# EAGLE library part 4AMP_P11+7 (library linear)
OP AMP

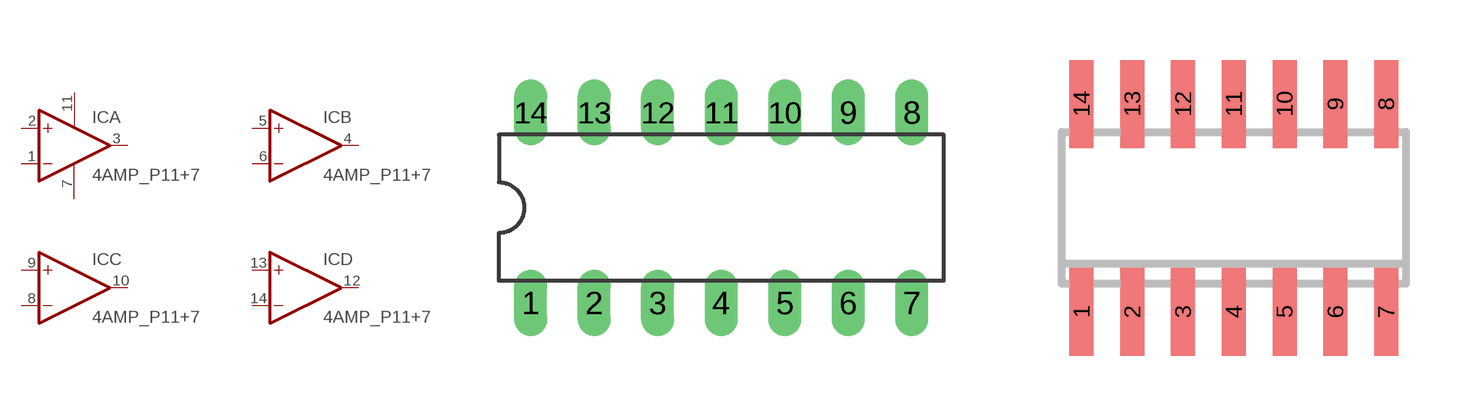
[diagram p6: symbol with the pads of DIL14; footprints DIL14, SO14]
Designator prefix IC; gates A=OPAMP B=OPAMP C=OPAMP D=OPAMP P=PWR+-

## 4AMP_P11+7N  [DIL14]
1  A:-IN  in
2  A:+IN  in
3  A:OUT  out
4  B:OUT  out
5  B:+IN  in
6  B:-IN  in
7  P:V-  pwr
8  C:-IN  in
9  C:+IN  in
10  C:OUT  out
11  P:V+  pwr
12  D:OUT  out
13  D:+IN  in
14  D:-IN  in

## 4AMP_P11+7D  [SO14]
Pads as for DIL14

## Footprint DIL14 (pad centres in mm)
Dual In Line Package
drill 0.813 long: 1 -7.62,-3.81; 2 -5.08,-3.81; 3 -2.54,-3.81; 4 0,-3.81; 5 2.54,-3.81; 6 5.08,-3.81; 7 7.62,-3.81; 8 7.62,3.81; 9 5.08,3.81; 10 2.54,3.81; 11 0,3.81; 12 -2.54,3.81; 13 -5.08,3.81; 14 -7.62,3.81

## Footprint SO14 (pad centres in mm)
Small Outline Package 14
smd 0.6 x 2.2: 1 -3.81,-2.6; 2 -2.54,-2.6; 3 -1.27,-2.6; 4 0,-2.6; 5 1.27,-2.6; 6 2.54,-2.6; 7 3.81,-2.6; 8 3.81,2.6; 9 2.54,2.6; 10 1.27,2.6; 11 0,2.6; 12 -1.27,2.6; 13 -2.54,2.6; 14 -3.81,2.6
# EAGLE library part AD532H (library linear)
MULTIPLIER

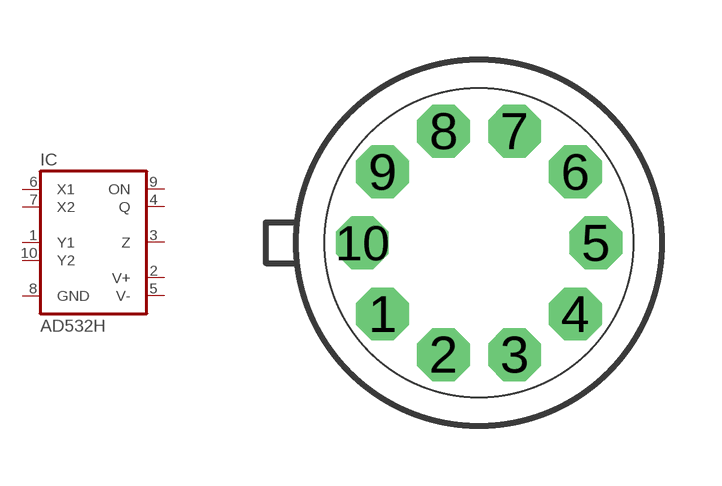
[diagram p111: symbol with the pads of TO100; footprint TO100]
Designator prefix IC

## AD532H  [TO100]
1  Y1  in
2  V+  pwr
3  Z  in
4  Q  out
5  V-  pwr
6  X1  in
7  X2  in
8  GND  pwr
9  ON  in
10  Y2  in

## Footprint TO100 (pad centres in mm)
Metal Can Package
drill 0.813 octagon: 1 -2.413,-1.778; 2 -0.889,-2.794; 3 0.889,-2.794; 4 2.413,-1.778; 5 2.921,0; 6 2.413,1.778; 7 0.889,2.794; 8 -0.889,2.794; 9 -2.413,1.778; 10 -2.921,0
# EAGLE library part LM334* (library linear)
3-Terminal Adjustable Current Sources Source: www.national.com/pf/LM/LM334.html | LM134.pdf

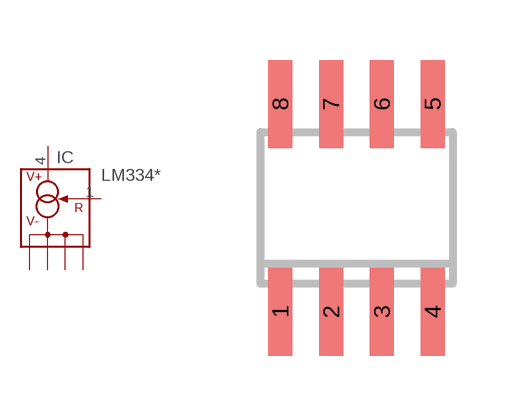
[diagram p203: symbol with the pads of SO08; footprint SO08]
Designator prefix IC

## LM334M, LM334MX  [SO08]
1  R  pas
2  V-  pas
3  V-  pas
4  V+  pas
6  V-  pas
7  V-  pas

## Footprint SO08 (pad centres in mm)
Small Outline Package 8 NS Package M08A
smd 0.6 x 2.2: 1 -1.905,-2.6; 2 -0.635,-2.6; 3 0.635,-2.6; 4 1.905,-2.6; 5 1.905,2.6; 6 0.635,2.6; 7 -0.635,2.6; 8 -1.905,2.6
